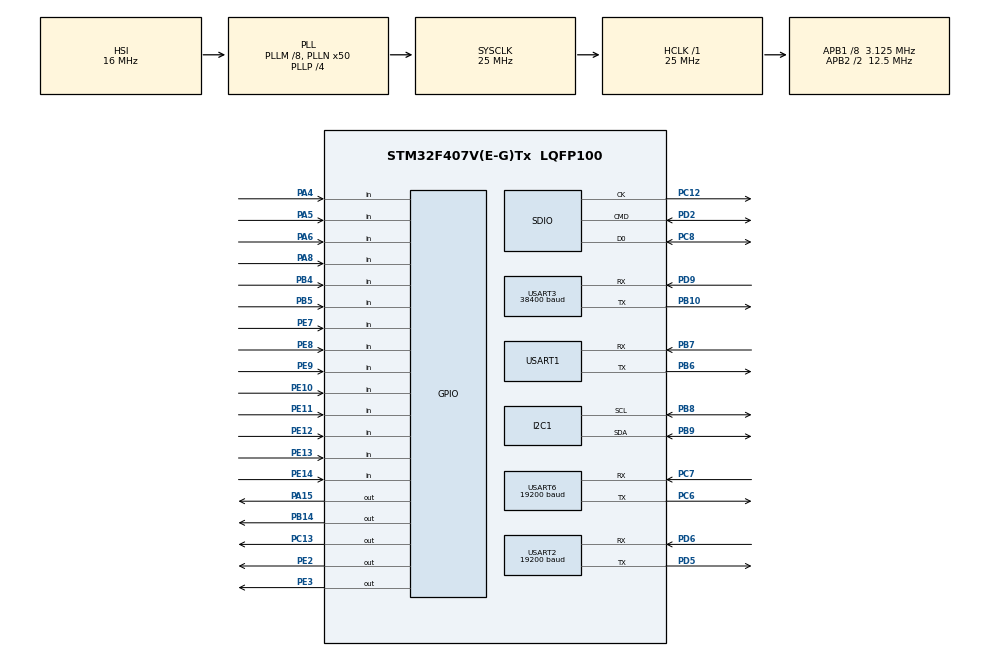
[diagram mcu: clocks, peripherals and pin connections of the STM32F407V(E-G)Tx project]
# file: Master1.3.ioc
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Mcu.Family=STM32F4
Mcu.Name=STM32F407V(E-G)Tx
Mcu.Package=LQFP100
NVIC.PriorityGroup=NVIC_PRIORITYGROUP_0
NVIC.USART1_IRQn=true\:0\:0\:false\:false\:true\:true\:true
NVIC.USART2_IRQn=true\:0\:0\:false\:false\:true\:true\:true
NVIC.USART3_IRQn=true\:0\:0\:false\:false\:true\:true\:true
NVIC.USART6_IRQn=true\:0\:0\:false\:false\:true\:true\:true
PA15.Signal=GPIO_Output
PA4.Signal=GPIO_Input
PA5.Signal=GPIO_Input
PA6.Signal=GPIO_Input
PA8.Signal=GPIO_Input
PB10.Mode=Asynchronous
PB10.Signal=USART3_TX
PB14.Signal=GPIO_Output
PB4.Signal=GPIO_Input
PB5.Signal=GPIO_Input
PB6.Mode=Asynchronous
PB6.Signal=USART1_TX
PB7.Mode=Asynchronous
PB7.Signal=USART1_RX
PB8.Mode=I2C
PB8.Signal=I2C1_SCL
PB9.Mode=I2C
PB9.Signal=I2C1_SDA
PC12.Mode=SD_1_bit
PC12.Signal=SDIO_CK
PC13-ANTI_TAMP.Signal=GPIO_Output
PC14-OSC32_IN.Mode=LSE-External-Oscillator
PC14-OSC32_IN.Signal=RCC_OSC32_IN
PC15-OSC32_OUT.Mode=LSE-External-Oscillator
PC15-OSC32_OUT.Signal=RCC_OSC32_OUT
PC6.Mode=Asynchronous
PC6.Signal=USART6_TX
PC7.Mode=Asynchronous
PC7.Signal=USART6_RX
PC8.GPIO_PuPd=GPIO_PULLUP
PC8.Mode=SD_1_bit
PC8.Signal=SDIO_D0
PD2.GPIO_PuPd=GPIO_PULLUP
PD2.Mode=SD_1_bit
PD2.Signal=SDIO_CMD
PD5.Mode=Asynchronous
PD5.Signal=USART2_TX
PD6.Mode=Asynchronous
PD6.Signal=USART2_RX
PD9.Mode=Asynchronous
PD9.Signal=USART3_RX
PE10.Signal=GPIO_Input
PE11.Signal=GPIO_Input
PE12.Signal=GPIO_Input
PE13.Signal=GPIO_Input
PE14.Signal=GPIO_Input
PE2.Signal=GPIO_Output
PE3.Signal=GPIO_Output
PE7.Signal=GPIO_Input
PE8.Signal=GPIO_Input
PE9.Signal=GPIO_Input
PH0-OSC_IN.Mode=HSE-External-Oscillator
PH0-OSC_IN.Signal=RCC_OSC_IN
PH1-OSC_OUT.Mode=HSE-External-Oscillator
PH1-OSC_OUT.Signal=RCC_OSC_OUT
ProjectManager.HeapSize=0x200
ProjectManager.StackSize=0x400
ProjectManager.TargetToolchain=TrueSTUDIO
RCC.48MHZClocksFreq_Value=14285714.285714285
RCC.AHBFreq_Value=25000000
RCC.APB1CLKDivider=RCC_HCLK_DIV8
RCC.APB1Freq_Value=3125000
RCC.APB1TimFreq_Value=6250000
RCC.APB2CLKDivider=RCC_HCLK_DIV2
RCC.APB2Freq_Value=12500000
RCC.APB2TimFreq_Value=25000000
RCC.CortexFreq_Value=25000000
RCC.HCLKFreq_Value=25000000
RCC.HSE_VALUE=8000000
RCC.HSI_VALUE=16000000
RCC.PLLM=8
RCC.PLLN=50
RCC.PLLP=RCC_PLLP_DIV4
RCC.PLLQ=7
RCC.RCC_RTC_Clock_Source=RCC_RTCCLKSOURCE_LSE
RCC.RCC_RTC_Clock_SourceVirtual=RCC_RTCCLKSOURCE_LSE
RCC.SYSCLKFreq_VALUE=25000000
RCC.SYSCLKSource=RCC_SYSCLKSOURCE_PLLCLK
RCC.VCOOutputFreq_Value=100000000
SDIO.ClockDiv=3
USART1.VirtualMode=VM_ASYNC
USART2.BaudRate=19200
USART2.VirtualMode=VM_ASYNC
USART3.BaudRate=38400
USART3.VirtualMode=VM_ASYNC
USART6.BaudRate=19200
USART6.VirtualMode=VM_ASYNC
VP_CRC_VS_CRC.Mode=CRC_Activate
VP_FATFS_VS_SDIO.Mode=SDIO
VP_RTC_VS_RTC_Activate.Mode=RTC_Enabled
board=STM32F4DISCOVERY

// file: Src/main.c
/* USER CODE BEGIN Header */
/**
  ******************************************************************************
  * @file           : main.c
  * @brief          : Main program body
  ******************************************************************************
  * @attention
  *
  * <h2><center>&copy; Copyright (c) 2019 STMicroelectronics.
  * All rights reserved.</center></h2>
  *
  * This software component is licensed by ST under BSD 3-Clause license,
  * the "License"; You may not use this file except in compliance with the
  * License. You may obtain a copy of the License at:
  *                        opensource.org/licenses/BSD-3-Clause
  *
  ***************************20/4/2020 **********implemented eeprom*****************************************
  */
  /*----------------------16/6/2020----------------implemented flash----refer readme.txt---------------------*/
/* USER CODE END Header */

#include "main.h"
#include "fatfs.h"

/* USER CODE BEGIN Includes */
#define EEPROM_ADDRESS 0x00A0

/* USER CODE END Includes */

CRC_HandleTypeDef hcrc;

I2C_HandleTypeDef hi2c1;

RTC_HandleTypeDef hrtc;

SD_HandleTypeDef hsd;

UART_HandleTypeDef huart1;
UART_HandleTypeDef huart2;
UART_HandleTypeDef huart3;
UART_HandleTypeDef huart6;

/* USER CODE BEGIN PV */
/* Private variables ---------------------------------------------------------*/
uint8_t dataToWrite=50;
uint8_t dataToRead[10];
/*------------SD card-------------*/
FATFS FatFs;
FRESULT fres;
 FIL fil;
 /*------------SD card-------------*/
 extern BYTE readBytes[150];
RTC_TimeTypeDef sTime;
RTC_DateTypeDef sDate;
__IO uint32_t TimingDelay;
__IO uint32_t TimingDelay1;
__IO uint32_t TimingDelay2;
__IO uint32_t TimingDelay3;
__IO uint32_t TimingDelay4;
__IO uint32_t TimingDelay5;
int msgUnPrcd;
int msgUnPrcd1;
int msgUnPrcd3;
int msgUnPrcd4;
int msgUnPrcd5;

uint8_t aRxBuffer[225];
uint8_t aRxBuffer1[225];
uint8_t aRxBuffer3[225];
uint8_t aRxBuffer4[225];
uint8_t aRxBuffer5[225];
extern uint8_t RecMsg1[250];
extern uint8_t RecMsg4[250];
extern uint8_t RecMsg2[250];
int signVal ;

int functionRec=0;
int secondLaserPinStatus;
int electricSupplyStatus;
int isGreen;
int isGreenLast;
 int laserPinStatusFlag;
 int sec=0;
 int signVal ;
 __IO uint32_t stringInt[25]; // string array to store messege received in uart
 __IO uint32_t CRCValue = 0;
 __IO uint8_t Disp[40];
 __IO uint8_t Disp1[40];
 __IO uint32_t crcbits = 0;
 char crcstring[4];
extern uint8_t Data[100] ;

 extern int laserPinStatus;
 int commFlag=0;
 int SDCardMsg=0;
 int min =0;
 extern int millisec;
 int millisec1;
 int CommCorrect=0;
 extern int serverMode;
 uint8_t side1;
 uint8_t side2;
 uint8_t side3;
 uint8_t side4;
 int slaveNo=1;
 int msgRec;
 int msgTx;

// int hundredPlaceSegment[5];
// int tenPlaceSegment[5];
// int unitPlaceSegment[5];

 uint8_t minLast ;
 int minCounter ;
 uint8_t planTime[50];
 int slave1Rsp=0;
 int slave2Rsp=0;
 int slave3Rsp=0;
 int slave4Rsp=0;
 uint8_t communicationStatus=0;

 int slave1Transmit=0;
 int slave2Transmit=0;
 int slave3Transmit=0;
 int slave4Transmit=0;
 extern  uint8_t aRxBuffer6[225];
/* USER CODE END PV */

void SystemClock_Config(void);
static void MX_GPIO_Init(void);
static void MX_RTC_Init(void);
static void MX_USART3_UART_Init(void);
static void MX_CRC_Init(void);
static void MX_SDIO_SD_Init(void);
static void MX_USART6_UART_Init(void);
static void MX_USART1_UART_Init(void);
static void MX_USART2_UART_Init(void);
static void MX_I2C1_Init(void);
/* USER CODE BEGIN PFP */
/* Private function prototypes -----------------------------------------------*/
void TimingDelay_Decrement();
void TimingDelay_Decrement1();
void TimingDelay_Decrement2();
void TimingDelay_Decrement3();
void TimingDelay_Decrement4();
void TimingDelay_Decrement5();

extern uint32_t HAL_CRC_Calculate(CRC_HandleTypeDef *hcrc, uint32_t pBuffer[], uint32_t BufferLength);
extern void transferRecValues(int cnt);
extern void transferRecValuesToData(int cnt);
extern void function6();
extern void function11();
extern void transferRec1ValuesToData(int cnt);
extern  void function10();
extern void clearingDataBuffer();
extern void  clearingDispBuffer();
extern void function3_1();
extern void function3_2();
extern void slaveSelection();
void clearaRxBuffer3();
void function10();
extern void program3();
extern void init4(void);
extern int function42(void);
extern void function8();
extern int function_10();
extern int function1();
extern int phaseInfoData(uint8_t planNo,uint8_t phaseNo);
extern  void function6_A();
extern void slaveResponse();
extern void sendMsgToSlave();
extern void espCommunication();
extern  void f0Communication();
extern void functionTransmitToSlave(uint8_t *sendFrame,uint8_t length);
extern void SDcardRead(char fileName[],int bytesToRead);
extern void SDcardWrite(char fileName[],int bytesToWrite,uint8_t *buffer );
extern void SDcardReadSeek(char fileName[],int bytesToRead,int seekBytes);
extern void SDcardWriteSeek(char fileName[],int bytesToWrite,uint8_t *buffer,int seekBytes );
extern int function4(void);
extern void analysingResponseOfSlave();
extern void enableGNZDAString();
extern void disableGNZDAString();
extern void diableAllString();
extern void leftGreen();
extern void getDateAndTimeFromGPS();
extern void readInputPin();
extern void checkServerFieldAction();
extern void writeI2C(uint16_t MemAddress,uint16_t MemAddSize,uint8_t *pData, uint16_t Size);
extern void readI2C(uint16_t MemAddress,uint16_t MemAddSize, uint8_t *pData,uint16_t Size);
extern void SDCardTruncateFile();

extern void sendData();
extern void flash_Erase();
extern int function18();
extern void populatePrimaryHVHorizontalHV();

int check=1;
int byte;
/* USER CODE END PFP */

/* USER CODE BEGIN 0 */
//FATFS FatFs;
//FRESULT fres;
// FIL fil;
//BYTE readBytes[100];
//TCHAR* rres;

/* USER CODE END 0 */

int main(void)
{

  /* MCU Configuration--------------------------------------------------------*/

  /* Reset of all peripherals, Initializes the Flash interface and the Systick. */
  HAL_Init();

  /* Configure the system clock */
  SystemClock_Config();

  /* Initialize all configured peripherals */
  MX_GPIO_Init();
  MX_RTC_Init();
  MX_USART3_UART_Init();
  MX_CRC_Init();
  MX_SDIO_SD_Init();
  MX_FATFS_Init();
  MX_USART6_UART_Init();
  MX_USART1_UART_Init();
  MX_USART2_UART_Init();
  MX_I2C1_Init();
  /* USER CODE BEGIN 2 */

         		    HAL_GPIO_WritePin(GPIOD, GPIO_PIN_4, GPIO_PIN_RESET);
         	       	HAL_GPIO_WritePin(GPIOD, GPIO_PIN_4, GPIO_PIN_SET);
         	       	HAL_GPIO_WritePin(GPIOD, GPIO_PIN_4, GPIO_PIN_RESET);
         	       	HAL_GPIO_WritePin(GPIOD, GPIO_PIN_5, GPIO_PIN_RESET);
         	        HAL_GPIO_WritePin(GPIOC, GPIO_PIN_13, GPIO_PIN_RESET);
//                    HAL_GPIO_WritePin(GPIOE, GPIO_PIN_1, GPIO_PIN_SET);
         	        HAL_GPIO_WritePin(GPIOE, GPIO_PIN_1, GPIO_PIN_RESET);
         	       HAL_GPIO_WritePin(GPIOE, GPIO_PIN_2, GPIO_PIN_RESET);
         	        HAL_GPIO_WritePin(GPIOE, GPIO_PIN_3, GPIO_PIN_RESET);
         	        HAL_GPIO_WritePin(GPIOE, GPIO_PIN_4, GPIO_PIN_RESET);
         	        HAL_GPIO_WritePin(GPIOE, GPIO_PIN_2, GPIO_PIN_SET);
         	        HAL_GPIO_WritePin(GPIOE, GPIO_PIN_3, GPIO_PIN_SET);
         	        HAL_GPIO_WritePin(GPIOE, GPIO_PIN_4, GPIO_PIN_SET);
         	       	/*--------------Mount SD card-----------------*/
         	       fres= f_mount(&FatFs, SDPath, 1);

//uint8_t data[6];
//data[0]='a';
//data[1]='b';
//data[2]='c';
//data[3]='d';
//data[4]='e';

//Flash_ReadByte(0x080E0000,data,6);

//
//                  flash_Erase();
//         	      Flash_Write( 0x080E0000,(uint8_t*) data ,5);

//         	      HAL_GPIO_WritePin(GPIOE, GPIO_PIN_1, GPIO_PIN_RESET);
//         	     HAL_GPIO_WritePin(GPIOE, GPIO_PIN_1, GPIO_PIN_SET);
//         	    HAL_GPIO_WritePin(GPIOE, GPIO_PIN_1, GPIO_PIN_RESET);
//         	   HAL_GPIO_WritePin(GPIOE, GPIO_PIN_1, GPIO_PIN_SET);

//getDateAndTimeFromGPS();
//         	      populatePrimaryHVHorizontalHV();
//         	      program3();
  /* USER CODE END 2 */

  /* Infinite loop */
  /* USER CODE BEGIN WHILE */
  while (1)
  {

	  init4();
//	  function18();

//
//	  HAL_UART_Receive_IT(&huart3, (uint8_t *)aRxBuffer3,1);//For ESP
//
//
//
//		if (msgUnPrcd3 == 1) {
//
//
//
//
//			sendData();
//
//
//		}

  }
  /* USER CODE END 3 */
}

void SystemClock_Config(void)
{
  RCC_OscInitTypeDef RCC_OscInitStruct = {0};
  RCC_ClkInitTypeDef RCC_ClkInitStruct = {0};
  RCC_PeriphCLKInitTypeDef PeriphClkInitStruct = {0};

  /** Configure the main internal regulator output voltage
  */
  __HAL_RCC_PWR_CLK_ENABLE();
  __HAL_PWR_VOLTAGESCALING_CONFIG(PWR_REGULATOR_VOLTAGE_SCALE1);
  /** Initializes the CPU, AHB and APB busses clocks
  */
  RCC_OscInitStruct.OscillatorType = RCC_OSCILLATORTYPE_HSI|RCC_OSCILLATORTYPE_LSE;
  RCC_OscInitStruct.LSEState = RCC_LSE_ON;
  RCC_OscInitStruct.HSIState = RCC_HSI_ON;
  RCC_OscInitStruct.HSICalibrationValue = RCC_HSICALIBRATION_DEFAULT;
  RCC_OscInitStruct.PLL.PLLState = RCC_PLL_ON;
  RCC_OscInitStruct.PLL.PLLSource = RCC_PLLSOURCE_HSI;
  RCC_OscInitStruct.PLL.PLLM = 8;
  RCC_OscInitStruct.PLL.PLLN = 50;
  RCC_OscInitStruct.PLL.PLLP = RCC_PLLP_DIV4;
  RCC_OscInitStruct.PLL.PLLQ = 7;
  if (HAL_RCC_OscConfig(&RCC_OscInitStruct) != HAL_OK)
  {
    Error_Handler();
  }
  /** Initializes the CPU, AHB and APB busses clocks
  */
  RCC_ClkInitStruct.ClockType = RCC_CLOCKTYPE_HCLK|RCC_CLOCKTYPE_SYSCLK
                              |RCC_CLOCKTYPE_PCLK1|RCC_CLOCKTYPE_PCLK2;
  RCC_ClkInitStruct.SYSCLKSource = RCC_SYSCLKSOURCE_PLLCLK;
  RCC_ClkInitStruct.AHBCLKDivider = RCC_SYSCLK_DIV1;
  RCC_ClkInitStruct.APB1CLKDivider = RCC_HCLK_DIV8;
  RCC_ClkInitStruct.APB2CLKDivider = RCC_HCLK_DIV2;

  if (HAL_RCC_ClockConfig(&RCC_ClkInitStruct, FLASH_LATENCY_0) != HAL_OK)
  {
    Error_Handler();
  }
  PeriphClkInitStruct.PeriphClockSelection = RCC_PERIPHCLK_RTC;
  PeriphClkInitStruct.RTCClockSelection = RCC_RTCCLKSOURCE_LSE;
  if (HAL_RCCEx_PeriphCLKConfig(&PeriphClkInitStruct) != HAL_OK)
  {
    Error_Handler();
  }
}

static void MX_CRC_Init(void)
{

  hcrc.Instance = CRC;
  if (HAL_CRC_Init(&hcrc) != HAL_OK)
  {
    Error_Handler();
  }

}

static void MX_I2C1_Init(void)
{

  hi2c1.Instance = I2C1;
  hi2c1.Init.ClockSpeed = 100000;
  hi2c1.Init.DutyCycle = I2C_DUTYCYCLE_2;
  hi2c1.Init.OwnAddress1 = 0;
  hi2c1.Init.AddressingMode = I2C_ADDRESSINGMODE_7BIT;
  hi2c1.Init.DualAddressMode = I2C_DUALADDRESS_DISABLE;
  hi2c1.Init.OwnAddress2 = 0;
  hi2c1.Init.GeneralCallMode = I2C_GENERALCALL_DISABLE;
  hi2c1.Init.NoStretchMode = I2C_NOSTRETCH_DISABLE;
  if (HAL_I2C_Init(&hi2c1) != HAL_OK)
  {
    Error_Handler();
  }

}

static void MX_RTC_Init(void)
{

  /** Initialize RTC Only
  */
  hrtc.Instance = RTC;
  hrtc.Init.HourFormat = RTC_HOURFORMAT_24;
  hrtc.Init.AsynchPrediv = 127;
  hrtc.Init.SynchPrediv = 255;
  hrtc.Init.OutPut = RTC_OUTPUT_DISABLE;
  hrtc.Init.OutPutPolarity = RTC_OUTPUT_POLARITY_HIGH;
  hrtc.Init.OutPutType = RTC_OUTPUT_TYPE_OPENDRAIN;
  if (HAL_RTC_Init(&hrtc) != HAL_OK)
  {
    Error_Handler();
  }

}

static void MX_SDIO_SD_Init(void)
{

  hsd.Instance = SDIO;
  hsd.Init.ClockEdge = SDIO_CLOCK_EDGE_RISING;
  hsd.Init.ClockBypass = SDIO_CLOCK_BYPASS_DISABLE;
  hsd.Init.ClockPowerSave = SDIO_CLOCK_POWER_SAVE_DISABLE;
  hsd.Init.BusWide = SDIO_BUS_WIDE_1B;
  hsd.Init.HardwareFlowControl = SDIO_HARDWARE_FLOW_CONTROL_DISABLE;
  hsd.Init.ClockDiv = 3;

}

static void MX_USART1_UART_Init(void)
{

  huart1.Instance = USART1;
  huart1.Init.BaudRate = 115200;
  huart1.Init.WordLength = UART_WORDLENGTH_8B;
  huart1.Init.StopBits = UART_STOPBITS_1;
  huart1.Init.Parity = UART_PARITY_NONE;
  huart1.Init.Mode = UART_MODE_TX_RX;
  huart1.Init.HwFlowCtl = UART_HWCONTROL_NONE;
  huart1.Init.OverSampling = UART_OVERSAMPLING_16;
  if (HAL_UART_Init(&huart1) != HAL_OK)
  {
    Error_Handler();
  }

}

static void MX_USART2_UART_Init(void)
{

  huart2.Instance = USART2;
  huart2.Init.BaudRate = 19200;
  huart2.Init.WordLength = UART_WORDLENGTH_8B;
  huart2.Init.StopBits = UART_STOPBITS_1;
  huart2.Init.Parity = UART_PARITY_NONE;
  huart2.Init.Mode = UART_MODE_TX_RX;
  huart2.Init.HwFlowCtl = UART_HWCONTROL_NONE;
  huart2.Init.OverSampling = UART_OVERSAMPLING_16;
  if (HAL_UART_Init(&huart2) != HAL_OK)
  {
    Error_Handler();
  }

}

static void MX_USART3_UART_Init(void)
{

  huart3.Instance = USART3;
  huart3.Init.BaudRate = 38400;
  huart3.Init.WordLength = UART_WORDLENGTH_8B;
  huart3.Init.StopBits = UART_STOPBITS_1;
  huart3.Init.Parity = UART_PARITY_NONE;
  huart3.Init.Mode = UART_MODE_TX_RX;
  huart3.Init.HwFlowCtl = UART_HWCONTROL_NONE;
  huart3.Init.OverSampling = UART_OVERSAMPLING_16;
  if (HAL_UART_Init(&huart3) != HAL_OK)
  {
    Error_Handler();
  }

}

static void MX_USART6_UART_Init(void)
{

  huart6.Instance = USART6;
  huart6.Init.BaudRate = 9600;
  huart6.Init.WordLength = UART_WORDLENGTH_8B;
  huart6.Init.StopBits = UART_STOPBITS_1;
  huart6.Init.Parity = UART_PARITY_NONE;
  huart6.Init.Mode = UART_MODE_TX_RX;
  huart6.Init.HwFlowCtl = UART_HWCONTROL_NONE;
  huart6.Init.OverSampling = UART_OVERSAMPLING_16;
  if (HAL_UART_Init(&huart6) != HAL_OK)
  {
    Error_Handler();
  }

}

static void MX_GPIO_Init(void)
{
  GPIO_InitTypeDef GPIO_InitStruct = {0};

  /* GPIO Ports Clock Enable */
  __HAL_RCC_GPIOE_CLK_ENABLE();
  __HAL_RCC_GPIOC_CLK_ENABLE();
  __HAL_RCC_GPIOH_CLK_ENABLE();
  __HAL_RCC_GPIOA_CLK_ENABLE();
  __HAL_RCC_GPIOB_CLK_ENABLE();
  __HAL_RCC_GPIOD_CLK_ENABLE();

  /*Configure GPIO pin Output Level */
  HAL_GPIO_WritePin(GPIOE, GPIO_PIN_4|GPIO_PIN_2|GPIO_PIN_3|GPIO_PIN_1, GPIO_PIN_RESET);

  /*Configure GPIO pin Output Level */
  HAL_GPIO_WritePin(GPIOC, GPIO_PIN_13|GPIO_PIN_3|GPIO_PIN_2, GPIO_PIN_RESET);

  /*Configure GPIO pin Output Level */
  HAL_GPIO_WritePin(GPIOB, GPIO_PIN_14|GPIO_PIN_3||GPIO_PIN_1, GPIO_PIN_RESET);

  /*Configure GPIO pin Output Level */
  HAL_GPIO_WritePin(GPIOA, GPIO_PIN_15|GPIO_PIN_3, GPIO_PIN_RESET);

  /*Configure GPIO pins : PE2 PE3 */
  GPIO_InitStruct.Pin = GPIO_PIN_2|GPIO_PIN_3|GPIO_PIN_1|GPIO_PIN_4;
  GPIO_InitStruct.Mode = GPIO_MODE_OUTPUT_PP;
  GPIO_InitStruct.Pull = GPIO_NOPULL;
  GPIO_InitStruct.Speed = GPIO_SPEED_FREQ_LOW;
  HAL_GPIO_Init(GPIOE, &GPIO_InitStruct);

  /*Configure GPIO pin : PC13 */
  GPIO_InitStruct.Pin = GPIO_PIN_13|GPIO_PIN_3|GPIO_PIN_2;
  GPIO_InitStruct.Mode = GPIO_MODE_OUTPUT_PP;
  GPIO_InitStruct.Pull = GPIO_NOPULL;
  GPIO_InitStruct.Speed = GPIO_SPEED_FREQ_LOW;
  HAL_GPIO_Init(GPIOC, &GPIO_InitStruct);

  /*Configure GPIO pins : PA4 PA5 PA6 PA8 */
  GPIO_InitStruct.Pin = GPIO_PIN_4|GPIO_PIN_5|GPIO_PIN_6|GPIO_PIN_8;
  GPIO_InitStruct.Mode = GPIO_MODE_INPUT;
  GPIO_InitStruct.Pull = GPIO_NOPULL;
  HAL_GPIO_Init(GPIOA, &GPIO_InitStruct);

  /*Configure GPIO pins : PE7 PE8 PE9 PE10
                           PE11 PE12 PE13 PE14 */
  GPIO_InitStruct.Pin = GPIO_PIN_7|GPIO_PIN_8|GPIO_PIN_9|GPIO_PIN_10
                          |GPIO_PIN_11|GPIO_PIN_12|GPIO_PIN_13|GPIO_PIN_14|GPIO_PIN_5;
  GPIO_InitStruct.Mode = GPIO_MODE_INPUT;
  GPIO_InitStruct.Pull = GPIO_PULLDOWN;//GPIO_NOPULL;
  HAL_GPIO_Init(GPIOE, &GPIO_InitStruct);

  /*Configure GPIO pin : PB14 */
  GPIO_InitStruct.Pin = GPIO_PIN_14|GPIO_PIN_3|GPIO_PIN_1;//PB1 is for shut down
  GPIO_InitStruct.Mode = GPIO_MODE_OUTPUT_PP;
  GPIO_InitStruct.Pull = GPIO_NOPULL;
  GPIO_InitStruct.Speed = GPIO_SPEED_FREQ_LOW;
  HAL_GPIO_Init(GPIOB, &GPIO_InitStruct);

  /*Configure GPIO pin : PA15 */
  GPIO_InitStruct.Pin = GPIO_PIN_15|GPIO_PIN_3;
  GPIO_InitStruct.Mode = GPIO_MODE_OUTPUT_PP;
  GPIO_InitStruct.Pull = GPIO_NOPULL;
  GPIO_InitStruct.Speed = GPIO_SPEED_FREQ_LOW;
  HAL_GPIO_Init(GPIOA, &GPIO_InitStruct);

  /*Configure GPIO pins : PB4 PB5 */
  GPIO_InitStruct.Pin = GPIO_PIN_4|GPIO_PIN_5; //for jump and extend
  GPIO_InitStruct.Mode = GPIO_MODE_INPUT;
  GPIO_InitStruct.Pull = GPIO_PULLUP;//GPIO_NOPULL;
  HAL_GPIO_Init(GPIOB, &GPIO_InitStruct);

  /*Configure GPIO pins : PE5 */
   GPIO_InitStruct.Pin = GPIO_PIN_5;
   GPIO_InitStruct.Mode = GPIO_MODE_INPUT;
   GPIO_InitStruct.Pull = GPIO_PULLUP;//GPIO_NOPULL;
   HAL_GPIO_Init(GPIOE, &GPIO_InitStruct);

}

/* USER CODE BEGIN 4 */
void TimingDelay_Decrement(void)
{
  if (TimingDelay != 0x00)
  {
    TimingDelay--;
  }
}
void TimingDelay_Decrement1(void)
{
  if (TimingDelay1 != 0x00)
  {
    TimingDelay1--;
  }
}
void TimingDelay_Decrement2(void)
{
  if (TimingDelay2 != 0x00)
  {
    TimingDelay2--;
  }
}
void TimingDelay_Decrement3(void)
{
  if (TimingDelay3 != 0x00)
  {
    TimingDelay3--;
  }
}
void TimingDelay_Decrement4(void)
{
  if (TimingDelay4 != 0x00)
  {
    TimingDelay4--;
  }
}
void TimingDelay_Decrement5(void)
{
  if (TimingDelay5 != 0x00)
  {
    TimingDelay5--;
  }
}
/* USER CODE END 4 */

void Error_Handler(void)
{
  while(1)
  {
  }
}

/************************ (C) COPYRIGHT STMicroelectronics *****END OF FILE****/
